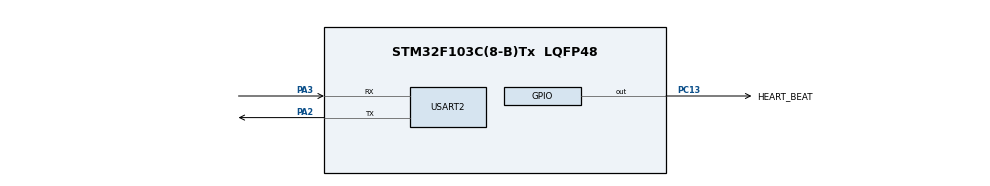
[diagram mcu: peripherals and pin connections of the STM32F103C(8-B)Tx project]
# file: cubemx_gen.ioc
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Mcu.Family=STM32F1
Mcu.Name=STM32F103C(8-B)Tx
Mcu.Package=LQFP48
NVIC.PriorityGroup=NVIC_PRIORITYGROUP_4
PA2.Mode=Asynchronous
PA2.Signal=USART2_TX
PA3.Mode=Asynchronous
PA3.Signal=USART2_RX
PC13-TAMPER-RTC.GPIO_Label=HEART_BEAT
PC13-TAMPER-RTC.Signal=GPIO_Output
ProjectManager.HeapSize=0x200
ProjectManager.StackSize=0x400
ProjectManager.TargetToolchain=Makefile
RCC.APB1Freq_Value=8000000
RCC.APB2Freq_Value=8000000
USART2.VirtualMode=VM_ASYNC
VP_SYS_VS_ND.Mode=No_Debug
board=custom

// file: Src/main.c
/* USER CODE BEGIN Header */
/**
  ******************************************************************************
  * @file           : main.c
  * @brief          : Main program body
  ******************************************************************************
  * @attention
  *
  * <h2><center>&copy; Copyright (c) 2020 STMicroelectronics.
  * All rights reserved.</center></h2>
  *
  * This software component is licensed by ST under BSD 3-Clause license,
  * the "License"; You may not use this file except in compliance with the
  * License. You may obtain a copy of the License at:
  *                        opensource.org/licenses/BSD-3-Clause
  *
  ******************************************************************************
  */
/* USER CODE END Header */

#include "main.h"

/* USER CODE BEGIN Includes */
#include "console_api.h"
#include "dbg_console_api.h"
#include <string.h>
/* USER CODE END Includes */

UART_HandleTypeDef huart2;

void SystemClock_Config(void);
static void MX_GPIO_Init(void);
static void MX_USART2_UART_Init(void);

int main(void)
{

  /* MCU Configuration--------------------------------------------------------*/

  /* Reset of all peripherals, Initializes the Flash interface and the Systick. */
  HAL_Init();

  /* Configure the system clock */
  SystemClock_Config();

  /* Initialize all configured peripherals */
  MX_GPIO_Init();
  MX_USART2_UART_Init();
  /* USER CODE BEGIN 2 */
  console_init(&huart2);
  /* USER CODE END 2 */

  /* Infinite loop */
  /* USER CODE BEGIN WHILE */
  while (1)
  {
    dbg_console_input_handling();
    /* USER CODE END WHILE */

  }
}

void SystemClock_Config(void)
{
  RCC_OscInitTypeDef RCC_OscInitStruct = {0};
  RCC_ClkInitTypeDef RCC_ClkInitStruct = {0};

  /** Configure the main internal regulator output voltage
  */
  __HAL_RCC_PWR_CLK_ENABLE();
  __HAL_PWR_VOLTAGESCALING_CONFIG(PWR_REGULATOR_VOLTAGE_SCALE3);
  /** Initializes the CPU, AHB and APB busses clocks
  */
  RCC_OscInitStruct.OscillatorType = RCC_OSCILLATORTYPE_HSI;
  RCC_OscInitStruct.HSIState = RCC_HSI_ON;
  RCC_OscInitStruct.HSICalibrationValue = RCC_HSICALIBRATION_DEFAULT;
  RCC_OscInitStruct.PLL.PLLState = RCC_PLL_ON;
  RCC_OscInitStruct.PLL.PLLSource = RCC_PLLSOURCE_HSI;
  RCC_OscInitStruct.PLL.PLLM = 16;
  RCC_OscInitStruct.PLL.PLLN = 336;
  RCC_OscInitStruct.PLL.PLLP = RCC_PLLP_DIV4;
  RCC_OscInitStruct.PLL.PLLQ = 2;
  RCC_OscInitStruct.PLL.PLLR = 2;
  if (HAL_RCC_OscConfig(&RCC_OscInitStruct) != HAL_OK)
  {
    Error_Handler();
  }
  /** Initializes the CPU, AHB and APB busses clocks
  */
  RCC_ClkInitStruct.ClockType = RCC_CLOCKTYPE_HCLK|RCC_CLOCKTYPE_SYSCLK
                              |RCC_CLOCKTYPE_PCLK1|RCC_CLOCKTYPE_PCLK2;
  RCC_ClkInitStruct.SYSCLKSource = RCC_SYSCLKSOURCE_PLLCLK;
  RCC_ClkInitStruct.AHBCLKDivider = RCC_SYSCLK_DIV1;
  RCC_ClkInitStruct.APB1CLKDivider = RCC_HCLK_DIV2;
  RCC_ClkInitStruct.APB2CLKDivider = RCC_HCLK_DIV1;

  if (HAL_RCC_ClockConfig(&RCC_ClkInitStruct, FLASH_LATENCY_2) != HAL_OK)
  {
    Error_Handler();
  }
}

static void MX_USART2_UART_Init(void)
{

  huart2.Instance = USART2;
  huart2.Init.BaudRate = 115200;
  huart2.Init.WordLength = UART_WORDLENGTH_8B;
  huart2.Init.StopBits = UART_STOPBITS_1;
  huart2.Init.Parity = UART_PARITY_NONE;
  huart2.Init.Mode = UART_MODE_TX_RX;
  huart2.Init.HwFlowCtl = UART_HWCONTROL_NONE;
  huart2.Init.OverSampling = UART_OVERSAMPLING_16;
  if (HAL_UART_Init(&huart2) != HAL_OK)
  {
    Error_Handler();
  }

}

static void MX_GPIO_Init(void)
{

  /* GPIO Ports Clock Enable */
  __HAL_RCC_GPIOA_CLK_ENABLE();

}

void Error_Handler(void)
{
}

/************************ (C) COPYRIGHT STMicroelectronics *****END OF FILE****/
